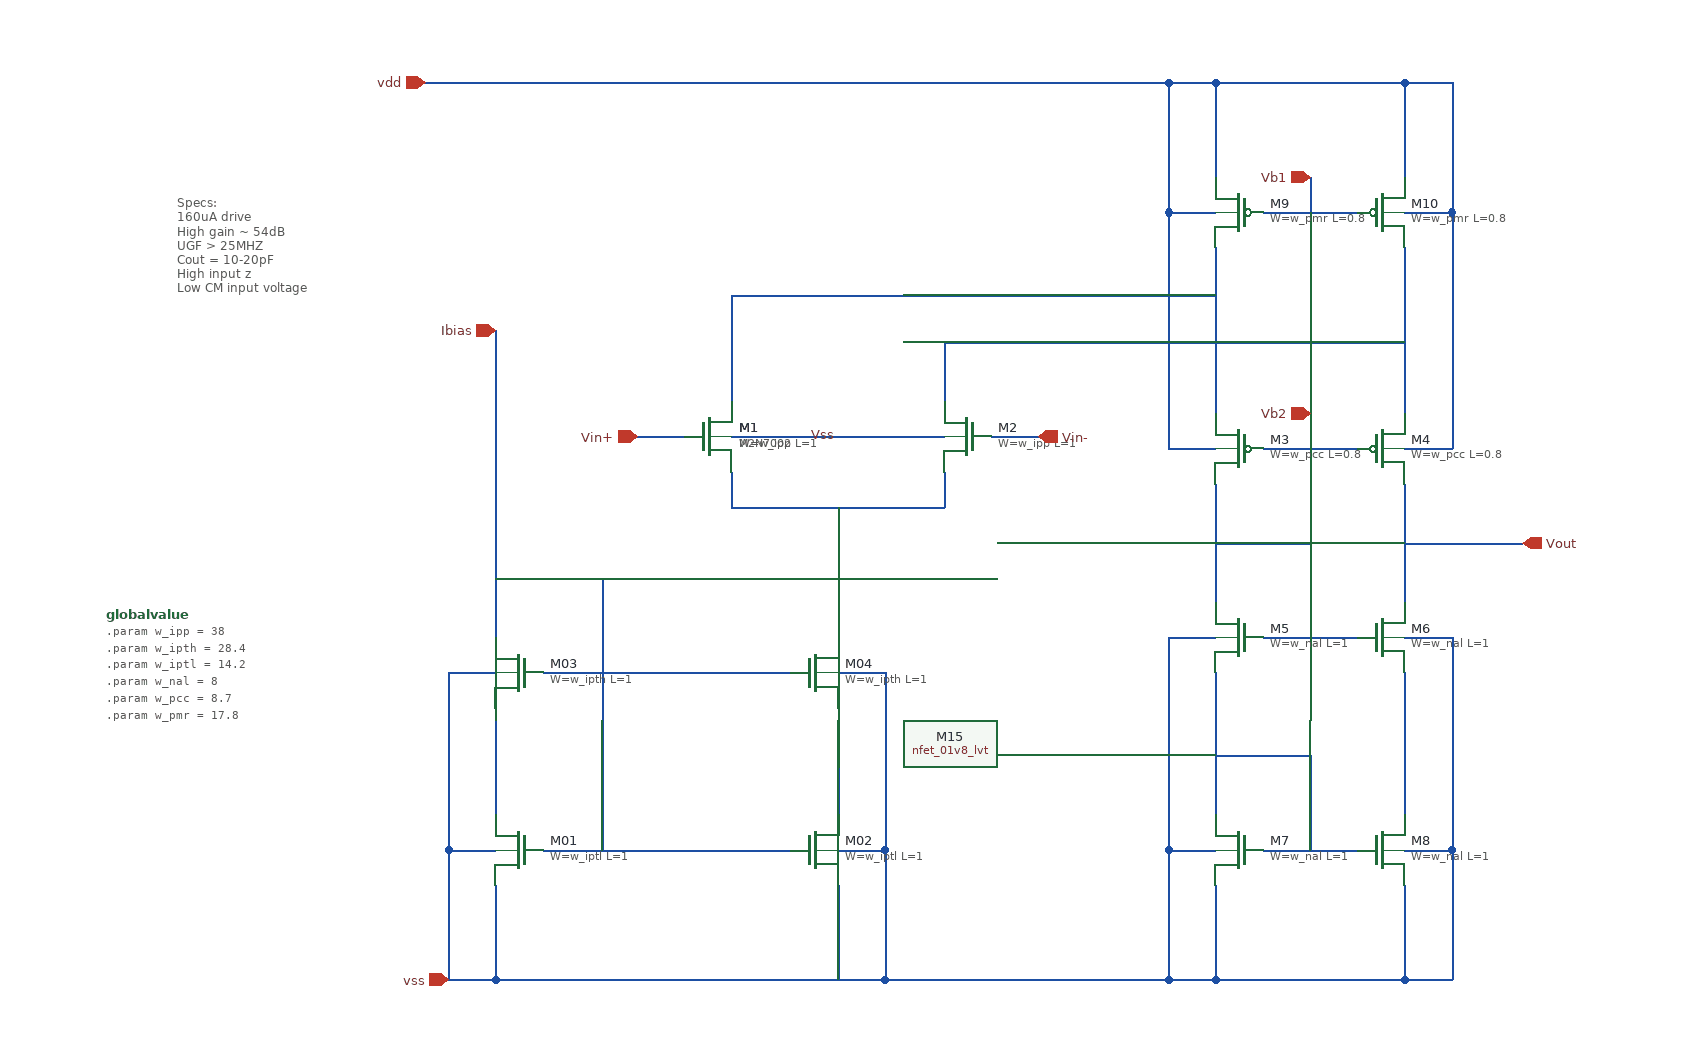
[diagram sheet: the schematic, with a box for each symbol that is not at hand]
v {xschem version=3.1.0 file_version=1.2
}
G {}
K {}
V {}
S {}
E {}
T {Specs:
160uA drive
High gain ~ 54dB
UGF > 25MHZ
Cout = 10-20pF
High input z
Low CM input voltage} 1800 -1070 0 0 0.3 0.3 {}
N 2200 -860 2230 -860 {
lab=Vin+}
N 2190 -860 2200 -860 {
lab=Vin+}
N 2490 -860 2500 -860 {
lab=Vin-}
N 2270 -830 2270 -800 {
lab=#net1}
N 2300 -800 2420 -800 {
lab=#net1}
N 2450 -830 2450 -800 {
lab=#net1}
N 2720 -850 2800 -850 {
lab=Vb2}
N 2720 -1050 2800 -1050 {
lab=Vb1}
N 2840 -970 2840 -880 {
lab=#net2}
N 2360 -800 2360 -690 {
lab=#net1}
N 2360 -630 2360 -590 {
lab=#net3}
N 2360 -590 2360 -540 {
lab=#net3}
N 2070 -620 2070 -540 {
lab=#net4}
N 2070 -630 2070 -620 {
lab=#net4}
N 2420 -800 2450 -800 {
lab=#net1}
N 2270 -800 2300 -800 {
lab=#net1}
N 2680 -1020 2680 -880 {
lab=#net5}
N 2840 -1020 2840 -970 {
lab=#net2}
N 2680 -1160 2680 -1080 {
lab=vdd}
N 2680 -1160 2840 -1160 {
lab=vdd}
N 2840 -1160 2840 -1080 {
lab=vdd}
N 2640 -1050 2680 -1050 {
lab=vdd}
N 2640 -1160 2640 -1050 {
lab=vdd}
N 2640 -1160 2680 -1160 {
lab=vdd}
N 2840 -1050 2880 -1050 {
lab=vdd}
N 2880 -1160 2880 -1050 {
lab=vdd}
N 2840 -1160 2880 -1160 {
lab=vdd}
N 2450 -940 2450 -890 {
lab=#net2}
N 2490 -940 2840 -940 {
lab=#net2}
N 2270 -980 2270 -890 {
lab=#net5}
N 2310 -980 2680 -980 {
lab=#net5}
N 2640 -850 2680 -850 {
lab=vdd}
N 2640 -1050 2640 -850 {
lab=vdd}
N 2840 -850 2880 -850 {
lab=vdd}
N 2880 -1050 2880 -850 {
lab=vdd}
N 2680 -820 2680 -720 {
lab=#net6}
N 2840 -820 2840 -720 {
lab=Vout}
N 2840 -660 2840 -540 {
lab=#net7}
N 2680 -660 2680 -540 {
lab=#net8}
N 2680 -480 2680 -400 {
lab=vss}
N 2680 -400 2840 -400 {
lab=vss}
N 2840 -480 2840 -400 {
lab=vss}
N 2840 -510 2880 -510 {
lab=vss}
N 2840 -400 2880 -400 {
lab=vss}
N 2880 -510 2880 -400 {
lab=vss}
N 2880 -690 2880 -510 {
lab=vss}
N 2840 -690 2880 -690 {
lab=vss}
N 2640 -690 2680 -690 {
lab=vss}
N 2640 -690 2640 -510 {
lab=vss}
N 2640 -510 2680 -510 {
lab=vss}
N 2640 -510 2680 -510 {
lab=vss}
N 2640 -510 2640 -400 {
lab=vss}
N 2640 -400 2680 -400 {
lab=vss}
N 2720 -690 2800 -690 {
lab=#net6}
N 2720 -510 2800 -510 {
lab=#net8}
N 2360 -480 2360 -400 {
lab=vss}
N 2400 -400 2640 -400 {
lab=vss}
N 2070 -400 2400 -400 {
lab=vss}
N 2070 -480 2070 -400 {
lab=vss}
N 2360 -510 2400 -510 {
lab=vss}
N 2400 -510 2400 -400 {
lab=vss}
N 2360 -660 2400 -660 {
lab=vss}
N 2400 -660 2400 -510 {
lab=vss}
N 2030 -660 2070 -660 {
lab=vss}
N 2030 -660 2030 -510 {
lab=vss}
N 2030 -510 2070 -510 {
lab=vss}
N 2030 -510 2070 -510 {
lab=vss}
N 2030 -510 2030 -400 {
lab=vss}
N 2030 -400 2070 -400 {
lab=vss}
N 2080 -1160 2640 -1160 {
lab=vdd}
N 2010 -1160 2080 -1160 {
lab=vdd}
N 2110 -660 2320 -660 {
lab=#net9}
N 2110 -510 2320 -510 {
lab=Ibias}
N 2500 -860 2530 -860 {
lab=Vin-}
N 2270 -980 2310 -980 {
lab=#net5}
N 2450 -940 2490 -940 {
lab=#net2}
N 2070 -950 2070 -680 {
lab=Ibias}
N 2840 -770 2940 -770 {
lab=Vout}
N 2760 -880 2760 -850 {
lab=Vb2}
N 2760 -1080 2760 -1050 {
lab=Vb1}
N 2270 -860 2450 -860 {
lab=Vss}
N 2070 -740 2160 -740 {
lab=Ibias}
N 2160 -740 2160 -510 {
lab=Ibias}
N 2680 -590 2760 -590 {
lab=#net8}
N 2680 -770 2760 -770 {
lab=#net6}
N 2760 -770 2760 -690 {
lab=#net6}
N 2760 -590 2760 -510 {
lab=#net8}
C {sky130_fd_pr/doc/nfet_01v8_lvt.svg} 2250 -860 0 0 {name=M1 model=M2N7002 device=2N7002 footprint=SOT23 m=1}
C {sky130_fd_pr/nfet_01v8_lvt.sym} 2250 -860 0 0 {name=M1
L=1
W=w_ipp
nf=1
mult=1
ad="'int((nf+1)/2) * W/nf * 0.29'" 
pd="'2*int((nf+1)/2) * (W/nf + 0.29)'"
as="'int((nf+2)/2) * W/nf * 0.29'" 
ps="'2*int((nf+2)/2) * (W/nf + 0.29)'"
nrd="'0.29 / W'" nrs="'0.29 / W'"
sa=0 sb=0 sd=0
model=nfet_01v8_lvt
spiceprefix=X
}
C {sky130_fd_pr/doc/nfet_01v8_lvt.svg} 2400 -860 0 1 {name=M15 model=M2N7002 device=2N7002 footprint=SOT23 m=1}
C {sky130_fd_pr/nfet_01v8_lvt.sym} 2470 -860 0 1 {name=M2
L=1
W=w_ipp
nf=1
mult=1
ad="'int((nf+1)/2) * W/nf * 0.29'" 
pd="'2*int((nf+1)/2) * (W/nf + 0.29)'"
as="'int((nf+2)/2) * W/nf * 0.29'" 
ps="'2*int((nf+2)/2) * (W/nf + 0.29)'"
nrd="'0.29 / W'" nrs="'0.29 / W'"
sa=0 sb=0 sd=0
model=nfet_01v8_lvt
spiceprefix=X
}
C {sky130_fd_pr/nfet_01v8.sym} 2340 -660 0 0 {name=M04
L=1
W=w_ipth
nf=1 
mult=1
ad="'int((nf+1)/2) * W/nf * 0.29'" 
pd="'2*int((nf+1)/2) * (W/nf + 0.29)'"
as="'int((nf+2)/2) * W/nf * 0.29'" 
ps="'2*int((nf+2)/2) * (W/nf + 0.29)'"
nrd="'0.29 / W'" nrs="'0.29 / W'"
sa=0 sb=0 sd=0
model=nfet_01v8
spiceprefix=X
}
C {sky130_fd_pr/nfet_01v8.sym} 2820 -690 0 0 {name=M6
L=1
W=w_nal
nf=1 
mult=1
ad="'int((nf+1)/2) * W/nf * 0.29'" 
pd="'2*int((nf+1)/2) * (W/nf + 0.29)'"
as="'int((nf+2)/2) * W/nf * 0.29'" 
ps="'2*int((nf+2)/2) * (W/nf + 0.29)'"
nrd="'0.29 / W'" nrs="'0.29 / W'"
sa=0 sb=0 sd=0
model=nfet_01v8
spiceprefix=X
}
C {sky130_fd_pr/nfet_01v8.sym} 2340 -510 0 0 {name=M02
L=1
W=w_iptl
nf=1 
mult=1
ad="'int((nf+1)/2) * W/nf * 0.29'" 
pd="'2*int((nf+1)/2) * (W/nf + 0.29)'"
as="'int((nf+2)/2) * W/nf * 0.29'" 
ps="'2*int((nf+2)/2) * (W/nf + 0.29)'"
nrd="'0.29 / W'" nrs="'0.29 / W'"
sa=0 sb=0 sd=0
model=nfet_01v8
spiceprefix=X
}
C {sky130_fd_pr/pfet_01v8_lvt.sym} 2820 -1050 0 0 {name=M10
L=0.8
W=w_pmr
nf=1
mult=1
ad="'int((nf+1)/2) * W/nf * 0.29'" 
pd="'2*int((nf+1)/2) * (W/nf + 0.29)'"
as="'int((nf+2)/2) * W/nf * 0.29'" 
ps="'2*int((nf+2)/2) * (W/nf + 0.29)'"
nrd="'0.29 / W'" nrs="'0.29 / W'"
sa=0 sb=0 sd=0
model=pfet_01v8_lvt
spiceprefix=X
}
C {sky130_fd_pr/nfet_01v8.sym} 2090 -660 0 1 {name=M03
L=1
W=w_ipth
nf=1 
mult=1
ad="'int((nf+1)/2) * W/nf * 0.29'" 
pd="'2*int((nf+1)/2) * (W/nf + 0.29)'"
as="'int((nf+2)/2) * W/nf * 0.29'" 
ps="'2*int((nf+2)/2) * (W/nf + 0.29)'"
nrd="'0.29 / W'" nrs="'0.29 / W'"
sa=0 sb=0 sd=0
model=nfet_01v8
spiceprefix=X
}
C {sky130_fd_pr/nfet_01v8.sym} 2090 -510 0 1 {name=M01
L=1
W=w_iptl
nf=1 
mult=1
ad="'int((nf+1)/2) * W/nf * 0.29'" 
pd="'2*int((nf+1)/2) * (W/nf + 0.29)'"
as="'int((nf+2)/2) * W/nf * 0.29'" 
ps="'2*int((nf+2)/2) * (W/nf + 0.29)'"
nrd="'0.29 / W'" nrs="'0.29 / W'"
sa=0 sb=0 sd=0
model=nfet_01v8
spiceprefix=X
}
C {sky130_fd_pr/nfet_01v8.sym} 2820 -510 0 0 {name=M8
L=1
W=w_nal
nf=1 
mult=1
ad="'int((nf+1)/2) * W/nf * 0.29'" 
pd="'2*int((nf+1)/2) * (W/nf + 0.29)'"
as="'int((nf+2)/2) * W/nf * 0.29'" 
ps="'2*int((nf+2)/2) * (W/nf + 0.29)'"
nrd="'0.29 / W'" nrs="'0.29 / W'"
sa=0 sb=0 sd=0
model=nfet_01v8
spiceprefix=X
}
C {sky130_fd_pr/nfet_01v8.sym} 2700 -690 0 1 {name=M5
L=1
W=w_nal
nf=1 
mult=1
ad="'int((nf+1)/2) * W/nf * 0.29'" 
pd="'2*int((nf+1)/2) * (W/nf + 0.29)'"
as="'int((nf+2)/2) * W/nf * 0.29'" 
ps="'2*int((nf+2)/2) * (W/nf + 0.29)'"
nrd="'0.29 / W'" nrs="'0.29 / W'"
sa=0 sb=0 sd=0
model=nfet_01v8
spiceprefix=X
}
C {sky130_fd_pr/nfet_01v8.sym} 2700 -510 0 1 {name=M7
L=1
W=w_nal
nf=1 
mult=1
ad="'int((nf+1)/2) * W/nf * 0.29'" 
pd="'2*int((nf+1)/2) * (W/nf + 0.29)'"
as="'int((nf+2)/2) * W/nf * 0.29'" 
ps="'2*int((nf+2)/2) * (W/nf + 0.29)'"
nrd="'0.29 / W'" nrs="'0.29 / W'"
sa=0 sb=0 sd=0
model=nfet_01v8
spiceprefix=X
}
C {sky130_fd_pr/pfet_01v8_lvt.sym} 2820 -850 0 0 {name=M4
L=0.8
W=w_pcc
nf=1
mult=1
ad="'int((nf+1)/2) * W/nf * 0.29'" 
pd="'2*int((nf+1)/2) * (W/nf + 0.29)'"
as="'int((nf+2)/2) * W/nf * 0.29'" 
ps="'2*int((nf+2)/2) * (W/nf + 0.29)'"
nrd="'0.29 / W'" nrs="'0.29 / W'"
sa=0 sb=0 sd=0
model=pfet_01v8_lvt
spiceprefix=X
}
C {sky130_fd_pr/pfet_01v8_lvt.sym} 2700 -1050 0 1 {name=M9
L=0.8
W=w_pmr
nf=1
mult=1
ad="'int((nf+1)/2) * W/nf * 0.29'" 
pd="'2*int((nf+1)/2) * (W/nf + 0.29)'"
as="'int((nf+2)/2) * W/nf * 0.29'" 
ps="'2*int((nf+2)/2) * (W/nf + 0.29)'"
nrd="'0.29 / W'" nrs="'0.29 / W'"
sa=0 sb=0 sd=0
model=pfet_01v8_lvt
spiceprefix=X
}
C {sky130_fd_pr/pfet_01v8_lvt.sym} 2700 -850 0 1 {name=M3
L=0.8
W=w_pcc
nf=1
mult=1
ad="'int((nf+1)/2) * W/nf * 0.29'" 
pd="'2*int((nf+1)/2) * (W/nf + 0.29)'"
as="'int((nf+2)/2) * W/nf * 0.29'" 
ps="'2*int((nf+2)/2) * (W/nf + 0.29)'"
nrd="'0.29 / W'" nrs="'0.29 / W'"
sa=0 sb=0 sd=0
model=pfet_01v8_lvt
spiceprefix=X
}
C {devices/iopin.sym} 2010 -1160 2 0 {name=p7 lab=vdd}
C {devices/iopin.sym} 2030 -400 2 0 {name=p2 lab=vss}
C {ipin.sym} 2190 -860 0 0 {name=p3 lab=Vin+
}
C {ipin.sym} 2530 -860 0 1 {name=p4 lab=Vin-

}
C {opin.sym} 2940 -770 0 0 {name=p1 lab=Vout
}
C {ipin.sym} 2760 -1080 1 0 {name=p5 lab=Vb1


}
C {ipin.sym} 2760 -880 1 0 {name=p6 lab=Vb2

}
C {lab_pin.sym} 2360 -860 1 0 {name=p8 sig_type=std_logic lab=Vss}
C {ipin.sym} 2070 -950 1 0 {name=p9 lab=Ibias



}
C {code_shown.sym} 1740 -710 0 0 {name=globalvalue only_toplevel=false value="

.param w_ipp = 38
.param w_ipth = 28.4
.param w_iptl = 14.2
.param w_nal = 8
.param w_pcc = 8.7
.param w_pmr = 17.8

"}
